VERSION 5.7 ;
  NOWIREEXTENSIONATPIN ON ;
  DIVIDERCHAR "/" ;
  BUSBITCHARS "[]" ;
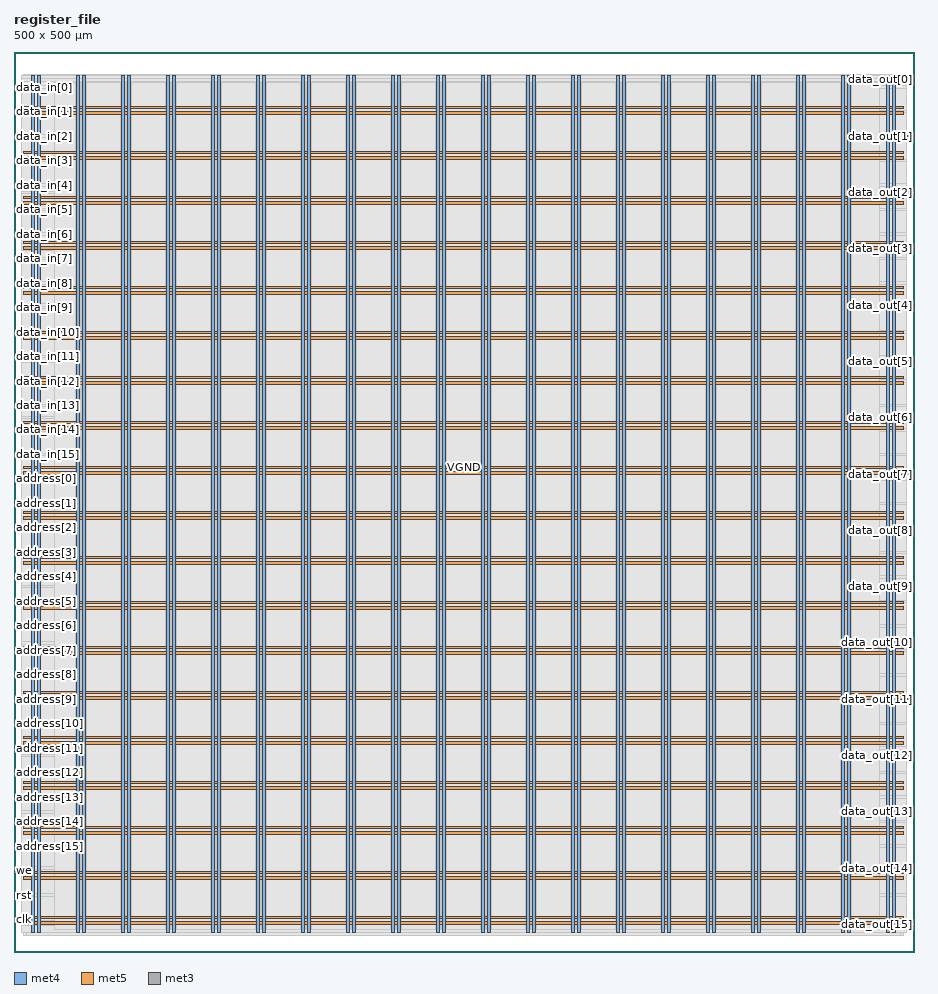
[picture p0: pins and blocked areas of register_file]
MACRO register_file
  CLASS BLOCK ;
  FOREIGN register_file ;
  ORIGIN 0.000 0.000 ;
  SIZE 500.000 BY 500.000 ;
  PIN VGND
    DIRECTION INOUT ;
    USE GROUND ;
    PORT
      LAYER met4 ;
        RECT 13.020 10.640 14.620 487.120 ;
    END
    PORT
      LAYER met4 ;
        RECT 38.020 10.640 39.620 487.120 ;
    END
    PORT
      LAYER met4 ;
        RECT 63.020 10.640 64.620 487.120 ;
    END
    PORT
      LAYER met4 ;
        RECT 88.020 10.640 89.620 487.120 ;
    END
    PORT
      LAYER met4 ;
        RECT 113.020 10.640 114.620 487.120 ;
    END
    PORT
      LAYER met4 ;
        RECT 138.020 10.640 139.620 487.120 ;
    END
    PORT
      LAYER met4 ;
        RECT 163.020 10.640 164.620 487.120 ;
    END
    PORT
      LAYER met4 ;
        RECT 188.020 10.640 189.620 487.120 ;
    END
    PORT
      LAYER met4 ;
        RECT 213.020 10.640 214.620 487.120 ;
    END
    PORT
      LAYER met4 ;
        RECT 238.020 10.640 239.620 487.120 ;
    END
    PORT
      LAYER met4 ;
        RECT 263.020 10.640 264.620 487.120 ;
    END
    PORT
      LAYER met4 ;
        RECT 288.020 10.640 289.620 487.120 ;
    END
    PORT
      LAYER met4 ;
        RECT 313.020 10.640 314.620 487.120 ;
    END
    PORT
      LAYER met4 ;
        RECT 338.020 10.640 339.620 487.120 ;
    END
    PORT
      LAYER met4 ;
        RECT 363.020 10.640 364.620 487.120 ;
    END
    PORT
      LAYER met4 ;
        RECT 388.020 10.640 389.620 487.120 ;
    END
    PORT
      LAYER met4 ;
        RECT 413.020 10.640 414.620 487.120 ;
    END
    PORT
      LAYER met4 ;
        RECT 438.020 10.640 439.620 487.120 ;
    END
    PORT
      LAYER met4 ;
        RECT 463.020 10.640 464.620 487.120 ;
    END
    PORT
      LAYER met4 ;
        RECT 488.020 10.640 489.620 487.120 ;
    END
    PORT
      LAYER met5 ;
        RECT 5.280 18.380 494.280 19.980 ;
    END
    PORT
      LAYER met5 ;
        RECT 5.280 43.380 494.280 44.980 ;
    END
    PORT
      LAYER met5 ;
        RECT 5.280 68.380 494.280 69.980 ;
    END
    PORT
      LAYER met5 ;
        RECT 5.280 93.380 494.280 94.980 ;
    END
    PORT
      LAYER met5 ;
        RECT 5.280 118.380 494.280 119.980 ;
    END
    PORT
      LAYER met5 ;
        RECT 5.280 143.380 494.280 144.980 ;
    END
    PORT
      LAYER met5 ;
        RECT 5.280 168.380 494.280 169.980 ;
    END
    PORT
      LAYER met5 ;
        RECT 5.280 193.380 494.280 194.980 ;
    END
    PORT
      LAYER met5 ;
        RECT 5.280 218.380 494.280 219.980 ;
    END
    PORT
      LAYER met5 ;
        RECT 5.280 243.380 494.280 244.980 ;
    END
    PORT
      LAYER met5 ;
        RECT 5.280 268.380 494.280 269.980 ;
    END
    PORT
      LAYER met5 ;
        RECT 5.280 293.380 494.280 294.980 ;
    END
    PORT
      LAYER met5 ;
        RECT 5.280 318.380 494.280 319.980 ;
    END
    PORT
      LAYER met5 ;
        RECT 5.280 343.380 494.280 344.980 ;
    END
    PORT
      LAYER met5 ;
        RECT 5.280 368.380 494.280 369.980 ;
    END
    PORT
      LAYER met5 ;
        RECT 5.280 393.380 494.280 394.980 ;
    END
    PORT
      LAYER met5 ;
        RECT 5.280 418.380 494.280 419.980 ;
    END
    PORT
      LAYER met5 ;
        RECT 5.280 443.380 494.280 444.980 ;
    END
    PORT
      LAYER met5 ;
        RECT 5.280 468.380 494.280 469.980 ;
    END
  END VGND
  PIN VPWR
    DIRECTION INOUT ;
    USE POWER ;
    PORT
      LAYER met4 ;
        RECT 9.720 10.640 11.320 487.120 ;
    END
    PORT
      LAYER met4 ;
        RECT 34.720 10.640 36.320 487.120 ;
    END
    PORT
      LAYER met4 ;
        RECT 59.720 10.640 61.320 487.120 ;
    END
    PORT
      LAYER met4 ;
        RECT 84.720 10.640 86.320 487.120 ;
    END
    PORT
      LAYER met4 ;
        RECT 109.720 10.640 111.320 487.120 ;
    END
    PORT
      LAYER met4 ;
        RECT 134.720 10.640 136.320 487.120 ;
    END
    PORT
      LAYER met4 ;
        RECT 159.720 10.640 161.320 487.120 ;
    END
    PORT
      LAYER met4 ;
        RECT 184.720 10.640 186.320 487.120 ;
    END
    PORT
      LAYER met4 ;
        RECT 209.720 10.640 211.320 487.120 ;
    END
    PORT
      LAYER met4 ;
        RECT 234.720 10.640 236.320 487.120 ;
    END
    PORT
      LAYER met4 ;
        RECT 259.720 10.640 261.320 487.120 ;
    END
    PORT
      LAYER met4 ;
        RECT 284.720 10.640 286.320 487.120 ;
    END
    PORT
      LAYER met4 ;
        RECT 309.720 10.640 311.320 487.120 ;
    END
    PORT
      LAYER met4 ;
        RECT 334.720 10.640 336.320 487.120 ;
    END
    PORT
      LAYER met4 ;
        RECT 359.720 10.640 361.320 487.120 ;
    END
    PORT
      LAYER met4 ;
        RECT 384.720 10.640 386.320 487.120 ;
    END
    PORT
      LAYER met4 ;
        RECT 409.720 10.640 411.320 487.120 ;
    END
    PORT
      LAYER met4 ;
        RECT 434.720 10.640 436.320 487.120 ;
    END
    PORT
      LAYER met4 ;
        RECT 459.720 10.640 461.320 487.120 ;
    END
    PORT
      LAYER met4 ;
        RECT 484.720 10.640 486.320 487.120 ;
    END
    PORT
      LAYER met5 ;
        RECT 5.280 15.080 494.280 16.680 ;
    END
    PORT
      LAYER met5 ;
        RECT 5.280 40.080 494.280 41.680 ;
    END
    PORT
      LAYER met5 ;
        RECT 5.280 65.080 494.280 66.680 ;
    END
    PORT
      LAYER met5 ;
        RECT 5.280 90.080 494.280 91.680 ;
    END
    PORT
      LAYER met5 ;
        RECT 5.280 115.080 494.280 116.680 ;
    END
    PORT
      LAYER met5 ;
        RECT 5.280 140.080 494.280 141.680 ;
    END
    PORT
      LAYER met5 ;
        RECT 5.280 165.080 494.280 166.680 ;
    END
    PORT
      LAYER met5 ;
        RECT 5.280 190.080 494.280 191.680 ;
    END
    PORT
      LAYER met5 ;
        RECT 5.280 215.080 494.280 216.680 ;
    END
    PORT
      LAYER met5 ;
        RECT 5.280 240.080 494.280 241.680 ;
    END
    PORT
      LAYER met5 ;
        RECT 5.280 265.080 494.280 266.680 ;
    END
    PORT
      LAYER met5 ;
        RECT 5.280 290.080 494.280 291.680 ;
    END
    PORT
      LAYER met5 ;
        RECT 5.280 315.080 494.280 316.680 ;
    END
    PORT
      LAYER met5 ;
        RECT 5.280 340.080 494.280 341.680 ;
    END
    PORT
      LAYER met5 ;
        RECT 5.280 365.080 494.280 366.680 ;
    END
    PORT
      LAYER met5 ;
        RECT 5.280 390.080 494.280 391.680 ;
    END
    PORT
      LAYER met5 ;
        RECT 5.280 415.080 494.280 416.680 ;
    END
    PORT
      LAYER met5 ;
        RECT 5.280 440.080 494.280 441.680 ;
    END
    PORT
      LAYER met5 ;
        RECT 5.280 465.080 494.280 466.680 ;
    END
  END VPWR
  PIN address[0]
    DIRECTION INPUT ;
    USE SIGNAL ;
    ANTENNAGATEAREA 3.813900 ;
    ANTENNADIFFAREA 3.042900 ;
    PORT
      LAYER met3 ;
        RECT 0.000 262.520 4.000 263.120 ;
    END
  END address[0]
  PIN address[10]
    DIRECTION INPUT ;
    USE SIGNAL ;
    PORT
      LAYER met3 ;
        RECT 0.000 126.520 4.000 127.120 ;
    END
  END address[10]
  PIN address[11]
    DIRECTION INPUT ;
    USE SIGNAL ;
    PORT
      LAYER met3 ;
        RECT 0.000 112.920 4.000 113.520 ;
    END
  END address[11]
  PIN address[12]
    DIRECTION INPUT ;
    USE SIGNAL ;
    PORT
      LAYER met3 ;
        RECT 0.000 99.320 4.000 99.920 ;
    END
  END address[12]
  PIN address[13]
    DIRECTION INPUT ;
    USE SIGNAL ;
    PORT
      LAYER met3 ;
        RECT 0.000 85.720 4.000 86.320 ;
    END
  END address[13]
  PIN address[14]
    DIRECTION INPUT ;
    USE SIGNAL ;
    PORT
      LAYER met3 ;
        RECT 0.000 72.120 4.000 72.720 ;
    END
  END address[14]
  PIN address[15]
    DIRECTION INPUT ;
    USE SIGNAL ;
    PORT
      LAYER met3 ;
        RECT 0.000 58.520 4.000 59.120 ;
    END
  END address[15]
  PIN address[1]
    DIRECTION INPUT ;
    USE SIGNAL ;
    ANTENNAGATEAREA 0.645000 ;
    PORT
      LAYER met3 ;
        RECT 0.000 248.920 4.000 249.520 ;
    END
  END address[1]
  PIN address[2]
    DIRECTION INPUT ;
    USE SIGNAL ;
    ANTENNAGATEAREA 0.322500 ;
    PORT
      LAYER met3 ;
        RECT 0.000 235.320 4.000 235.920 ;
    END
  END address[2]
  PIN address[3]
    DIRECTION INPUT ;
    USE SIGNAL ;
    ANTENNAGATEAREA 2.573700 ;
    ANTENNADIFFAREA 0.434700 ;
    PORT
      LAYER met3 ;
        RECT 0.000 221.720 4.000 222.320 ;
    END
  END address[3]
  PIN address[4]
    DIRECTION INPUT ;
    USE SIGNAL ;
    PORT
      LAYER met3 ;
        RECT 0.000 208.120 4.000 208.720 ;
    END
  END address[4]
  PIN address[5]
    DIRECTION INPUT ;
    USE SIGNAL ;
    PORT
      LAYER met3 ;
        RECT 0.000 194.520 4.000 195.120 ;
    END
  END address[5]
  PIN address[6]
    DIRECTION INPUT ;
    USE SIGNAL ;
    PORT
      LAYER met3 ;
        RECT 0.000 180.920 4.000 181.520 ;
    END
  END address[6]
  PIN address[7]
    DIRECTION INPUT ;
    USE SIGNAL ;
    PORT
      LAYER met3 ;
        RECT 0.000 167.320 4.000 167.920 ;
    END
  END address[7]
  PIN address[8]
    DIRECTION INPUT ;
    USE SIGNAL ;
    PORT
      LAYER met3 ;
        RECT 0.000 153.720 4.000 154.320 ;
    END
  END address[8]
  PIN address[9]
    DIRECTION INPUT ;
    USE SIGNAL ;
    PORT
      LAYER met3 ;
        RECT 0.000 140.120 4.000 140.720 ;
    END
  END address[9]
  PIN clk
    DIRECTION INPUT ;
    USE SIGNAL ;
    ANTENNAGATEAREA 1.286700 ;
    ANTENNADIFFAREA 0.434700 ;
    PORT
      LAYER met3 ;
        RECT 0.000 17.720 4.000 18.320 ;
    END
  END clk
  PIN data_in[0]
    DIRECTION INPUT ;
    USE SIGNAL ;
    ANTENNAGATEAREA 1.681500 ;
    PORT
      LAYER met3 ;
        RECT 0.000 480.120 4.000 480.720 ;
    END
  END data_in[0]
  PIN data_in[10]
    DIRECTION INPUT ;
    USE SIGNAL ;
    ANTENNAGATEAREA 1.681500 ;
    PORT
      LAYER met3 ;
        RECT 0.000 344.120 4.000 344.720 ;
    END
  END data_in[10]
  PIN data_in[11]
    DIRECTION INPUT ;
    USE SIGNAL ;
    ANTENNAGATEAREA 2.985600 ;
    ANTENNADIFFAREA 1.304100 ;
    PORT
      LAYER met3 ;
        RECT 0.000 330.520 4.000 331.120 ;
    END
  END data_in[11]
  PIN data_in[12]
    DIRECTION INPUT ;
    USE SIGNAL ;
    ANTENNAGATEAREA 1.681500 ;
    PORT
      LAYER met3 ;
        RECT 0.000 316.920 4.000 317.520 ;
    END
  END data_in[12]
  PIN data_in[13]
    DIRECTION INPUT ;
    USE SIGNAL ;
    ANTENNAGATEAREA 1.681500 ;
    PORT
      LAYER met3 ;
        RECT 0.000 303.320 4.000 303.920 ;
    END
  END data_in[13]
  PIN data_in[14]
    DIRECTION INPUT ;
    USE SIGNAL ;
    ANTENNAGATEAREA 1.681500 ;
    PORT
      LAYER met3 ;
        RECT 0.000 289.720 4.000 290.320 ;
    END
  END data_in[14]
  PIN data_in[15]
    DIRECTION INPUT ;
    USE SIGNAL ;
    ANTENNAGATEAREA 1.681500 ;
    PORT
      LAYER met3 ;
        RECT 0.000 276.120 4.000 276.720 ;
    END
  END data_in[15]
  PIN data_in[1]
    DIRECTION INPUT ;
    USE SIGNAL ;
    ANTENNAGATEAREA 2.550900 ;
    ANTENNADIFFAREA 0.869400 ;
    PORT
      LAYER met3 ;
        RECT 0.000 466.520 4.000 467.120 ;
    END
  END data_in[1]
  PIN data_in[2]
    DIRECTION INPUT ;
    USE SIGNAL ;
    ANTENNAGATEAREA 1.681500 ;
    PORT
      LAYER met3 ;
        RECT 0.000 452.920 4.000 453.520 ;
    END
  END data_in[2]
  PIN data_in[3]
    DIRECTION INPUT ;
    USE SIGNAL ;
    ANTENNAGATEAREA 1.681500 ;
    PORT
      LAYER met3 ;
        RECT 0.000 439.320 4.000 439.920 ;
    END
  END data_in[3]
  PIN data_in[4]
    DIRECTION INPUT ;
    USE SIGNAL ;
    ANTENNAGATEAREA 1.681500 ;
    PORT
      LAYER met3 ;
        RECT 0.000 425.720 4.000 426.320 ;
    END
  END data_in[4]
  PIN data_in[5]
    DIRECTION INPUT ;
    USE SIGNAL ;
    ANTENNAGATEAREA 2.550900 ;
    ANTENNADIFFAREA 0.869400 ;
    PORT
      LAYER met3 ;
        RECT 0.000 412.120 4.000 412.720 ;
    END
  END data_in[5]
  PIN data_in[6]
    DIRECTION INPUT ;
    USE SIGNAL ;
    ANTENNAGATEAREA 1.681500 ;
    PORT
      LAYER met3 ;
        RECT 0.000 398.520 4.000 399.120 ;
    END
  END data_in[6]
  PIN data_in[7]
    DIRECTION INPUT ;
    USE SIGNAL ;
    ANTENNAGATEAREA 1.681500 ;
    PORT
      LAYER met3 ;
        RECT 0.000 384.920 4.000 385.520 ;
    END
  END data_in[7]
  PIN data_in[8]
    DIRECTION INPUT ;
    USE SIGNAL ;
    ANTENNAGATEAREA 1.681500 ;
    PORT
      LAYER met3 ;
        RECT 0.000 371.320 4.000 371.920 ;
    END
  END data_in[8]
  PIN data_in[9]
    DIRECTION INPUT ;
    USE SIGNAL ;
    ANTENNAGATEAREA 1.681500 ;
    PORT
      LAYER met3 ;
        RECT 0.000 357.720 4.000 358.320 ;
    END
  END data_in[9]
  PIN data_out[0]
    DIRECTION OUTPUT TRISTATE ;
    USE SIGNAL ;
    ANTENNADIFFAREA 0.445500 ;
    PORT
      LAYER met3 ;
        RECT 496.000 484.200 500.000 484.800 ;
    END
  END data_out[0]
  PIN data_out[10]
    DIRECTION OUTPUT TRISTATE ;
    USE SIGNAL ;
    ANTENNADIFFAREA 0.445500 ;
    PORT
      LAYER met3 ;
        RECT 496.000 171.400 500.000 172.000 ;
    END
  END data_out[10]
  PIN data_out[11]
    DIRECTION OUTPUT TRISTATE ;
    USE SIGNAL ;
    ANTENNADIFFAREA 0.445500 ;
    PORT
      LAYER met3 ;
        RECT 496.000 140.120 500.000 140.720 ;
    END
  END data_out[11]
  PIN data_out[12]
    DIRECTION OUTPUT TRISTATE ;
    USE SIGNAL ;
    ANTENNADIFFAREA 0.445500 ;
    PORT
      LAYER met3 ;
        RECT 496.000 108.840 500.000 109.440 ;
    END
  END data_out[12]
  PIN data_out[13]
    DIRECTION OUTPUT TRISTATE ;
    USE SIGNAL ;
    ANTENNADIFFAREA 0.445500 ;
    PORT
      LAYER met3 ;
        RECT 496.000 77.560 500.000 78.160 ;
    END
  END data_out[13]
  PIN data_out[14]
    DIRECTION OUTPUT TRISTATE ;
    USE SIGNAL ;
    ANTENNADIFFAREA 0.445500 ;
    PORT
      LAYER met3 ;
        RECT 496.000 46.280 500.000 46.880 ;
    END
  END data_out[14]
  PIN data_out[15]
    DIRECTION OUTPUT TRISTATE ;
    USE SIGNAL ;
    ANTENNADIFFAREA 0.445500 ;
    PORT
      LAYER met3 ;
        RECT 496.000 15.000 500.000 15.600 ;
    END
  END data_out[15]
  PIN data_out[1]
    DIRECTION OUTPUT TRISTATE ;
    USE SIGNAL ;
    ANTENNADIFFAREA 0.445500 ;
    PORT
      LAYER met3 ;
        RECT 496.000 452.920 500.000 453.520 ;
    END
  END data_out[1]
  PIN data_out[2]
    DIRECTION OUTPUT TRISTATE ;
    USE SIGNAL ;
    ANTENNADIFFAREA 0.445500 ;
    PORT
      LAYER met3 ;
        RECT 496.000 421.640 500.000 422.240 ;
    END
  END data_out[2]
  PIN data_out[3]
    DIRECTION OUTPUT TRISTATE ;
    USE SIGNAL ;
    ANTENNADIFFAREA 0.445500 ;
    PORT
      LAYER met3 ;
        RECT 496.000 390.360 500.000 390.960 ;
    END
  END data_out[3]
  PIN data_out[4]
    DIRECTION OUTPUT TRISTATE ;
    USE SIGNAL ;
    ANTENNADIFFAREA 0.445500 ;
    PORT
      LAYER met3 ;
        RECT 496.000 359.080 500.000 359.680 ;
    END
  END data_out[4]
  PIN data_out[5]
    DIRECTION OUTPUT TRISTATE ;
    USE SIGNAL ;
    ANTENNADIFFAREA 0.445500 ;
    PORT
      LAYER met3 ;
        RECT 496.000 327.800 500.000 328.400 ;
    END
  END data_out[5]
  PIN data_out[6]
    DIRECTION OUTPUT TRISTATE ;
    USE SIGNAL ;
    ANTENNADIFFAREA 0.445500 ;
    PORT
      LAYER met3 ;
        RECT 496.000 296.520 500.000 297.120 ;
    END
  END data_out[6]
  PIN data_out[7]
    DIRECTION OUTPUT TRISTATE ;
    USE SIGNAL ;
    ANTENNADIFFAREA 0.445500 ;
    PORT
      LAYER met3 ;
        RECT 496.000 265.240 500.000 265.840 ;
    END
  END data_out[7]
  PIN data_out[8]
    DIRECTION OUTPUT TRISTATE ;
    USE SIGNAL ;
    ANTENNADIFFAREA 0.445500 ;
    PORT
      LAYER met3 ;
        RECT 496.000 233.960 500.000 234.560 ;
    END
  END data_out[8]
  PIN data_out[9]
    DIRECTION OUTPUT TRISTATE ;
    USE SIGNAL ;
    ANTENNADIFFAREA 0.445500 ;
    PORT
      LAYER met3 ;
        RECT 496.000 202.680 500.000 203.280 ;
    END
  END data_out[9]
  PIN rst
    DIRECTION INPUT ;
    USE SIGNAL ;
    ANTENNAGATEAREA 1.812900 ;
    ANTENNADIFFAREA 0.869400 ;
    PORT
      LAYER met3 ;
        RECT 0.000 31.320 4.000 31.920 ;
    END
  END rst
  PIN we
    DIRECTION INPUT ;
    USE SIGNAL ;
    ANTENNAGATEAREA 4.233600 ;
    ANTENNADIFFAREA 3.477600 ;
    PORT
      LAYER met3 ;
        RECT 0.000 44.920 4.000 45.520 ;
    END
  END we
  OBS
      LAYER li1 ;
        RECT 5.520 10.795 494.040 486.965 ;
      LAYER met1 ;
        RECT 5.520 9.220 494.040 487.520 ;
      LAYER met2 ;
        RECT 7.000 9.190 492.560 487.550 ;
      LAYER met3 ;
        RECT 4.000 485.200 496.000 487.045 ;
        RECT 4.000 483.800 495.600 485.200 ;
        RECT 4.000 481.120 496.000 483.800 ;
        RECT 4.400 479.720 496.000 481.120 ;
        RECT 4.000 467.520 496.000 479.720 ;
        RECT 4.400 466.120 496.000 467.520 ;
        RECT 4.000 453.920 496.000 466.120 ;
        RECT 4.400 452.520 495.600 453.920 ;
        RECT 4.000 440.320 496.000 452.520 ;
        RECT 4.400 438.920 496.000 440.320 ;
        RECT 4.000 426.720 496.000 438.920 ;
        RECT 4.400 425.320 496.000 426.720 ;
        RECT 4.000 422.640 496.000 425.320 ;
        RECT 4.000 421.240 495.600 422.640 ;
        RECT 4.000 413.120 496.000 421.240 ;
        RECT 4.400 411.720 496.000 413.120 ;
        RECT 4.000 399.520 496.000 411.720 ;
        RECT 4.400 398.120 496.000 399.520 ;
        RECT 4.000 391.360 496.000 398.120 ;
        RECT 4.000 389.960 495.600 391.360 ;
        RECT 4.000 385.920 496.000 389.960 ;
        RECT 4.400 384.520 496.000 385.920 ;
        RECT 4.000 372.320 496.000 384.520 ;
        RECT 4.400 370.920 496.000 372.320 ;
        RECT 4.000 360.080 496.000 370.920 ;
        RECT 4.000 358.720 495.600 360.080 ;
        RECT 4.400 358.680 495.600 358.720 ;
        RECT 4.400 357.320 496.000 358.680 ;
        RECT 4.000 345.120 496.000 357.320 ;
        RECT 4.400 343.720 496.000 345.120 ;
        RECT 4.000 331.520 496.000 343.720 ;
        RECT 4.400 330.120 496.000 331.520 ;
        RECT 4.000 328.800 496.000 330.120 ;
        RECT 4.000 327.400 495.600 328.800 ;
        RECT 4.000 317.920 496.000 327.400 ;
        RECT 4.400 316.520 496.000 317.920 ;
        RECT 4.000 304.320 496.000 316.520 ;
        RECT 4.400 302.920 496.000 304.320 ;
        RECT 4.000 297.520 496.000 302.920 ;
        RECT 4.000 296.120 495.600 297.520 ;
        RECT 4.000 290.720 496.000 296.120 ;
        RECT 4.400 289.320 496.000 290.720 ;
        RECT 4.000 277.120 496.000 289.320 ;
        RECT 4.400 275.720 496.000 277.120 ;
        RECT 4.000 266.240 496.000 275.720 ;
        RECT 4.000 264.840 495.600 266.240 ;
        RECT 4.000 263.520 496.000 264.840 ;
        RECT 4.400 262.120 496.000 263.520 ;
        RECT 4.000 249.920 496.000 262.120 ;
        RECT 4.400 248.520 496.000 249.920 ;
        RECT 4.000 236.320 496.000 248.520 ;
        RECT 4.400 234.960 496.000 236.320 ;
        RECT 4.400 234.920 495.600 234.960 ;
        RECT 4.000 233.560 495.600 234.920 ;
        RECT 4.000 222.720 496.000 233.560 ;
        RECT 4.400 221.320 496.000 222.720 ;
        RECT 4.000 209.120 496.000 221.320 ;
        RECT 4.400 207.720 496.000 209.120 ;
        RECT 4.000 203.680 496.000 207.720 ;
        RECT 4.000 202.280 495.600 203.680 ;
        RECT 4.000 195.520 496.000 202.280 ;
        RECT 4.400 194.120 496.000 195.520 ;
        RECT 4.000 181.920 496.000 194.120 ;
        RECT 4.400 180.520 496.000 181.920 ;
        RECT 4.000 172.400 496.000 180.520 ;
        RECT 4.000 171.000 495.600 172.400 ;
        RECT 4.000 168.320 496.000 171.000 ;
        RECT 4.400 166.920 496.000 168.320 ;
        RECT 4.000 154.720 496.000 166.920 ;
        RECT 4.400 153.320 496.000 154.720 ;
        RECT 4.000 141.120 496.000 153.320 ;
        RECT 4.400 139.720 495.600 141.120 ;
        RECT 4.000 127.520 496.000 139.720 ;
        RECT 4.400 126.120 496.000 127.520 ;
        RECT 4.000 113.920 496.000 126.120 ;
        RECT 4.400 112.520 496.000 113.920 ;
        RECT 4.000 109.840 496.000 112.520 ;
        RECT 4.000 108.440 495.600 109.840 ;
        RECT 4.000 100.320 496.000 108.440 ;
        RECT 4.400 98.920 496.000 100.320 ;
        RECT 4.000 86.720 496.000 98.920 ;
        RECT 4.400 85.320 496.000 86.720 ;
        RECT 4.000 78.560 496.000 85.320 ;
        RECT 4.000 77.160 495.600 78.560 ;
        RECT 4.000 73.120 496.000 77.160 ;
        RECT 4.400 71.720 496.000 73.120 ;
        RECT 4.000 59.520 496.000 71.720 ;
        RECT 4.400 58.120 496.000 59.520 ;
        RECT 4.000 47.280 496.000 58.120 ;
        RECT 4.000 45.920 495.600 47.280 ;
        RECT 4.400 45.880 495.600 45.920 ;
        RECT 4.400 44.520 496.000 45.880 ;
        RECT 4.000 32.320 496.000 44.520 ;
        RECT 4.400 30.920 496.000 32.320 ;
        RECT 4.000 18.720 496.000 30.920 ;
        RECT 4.400 17.320 496.000 18.720 ;
        RECT 4.000 16.000 496.000 17.320 ;
        RECT 4.000 14.600 495.600 16.000 ;
        RECT 4.000 10.715 496.000 14.600 ;
      LAYER met4 ;
        RECT 22.375 12.415 34.320 483.305 ;
        RECT 36.720 12.415 37.620 483.305 ;
        RECT 40.020 12.415 59.320 483.305 ;
        RECT 61.720 12.415 62.620 483.305 ;
        RECT 65.020 12.415 84.320 483.305 ;
        RECT 86.720 12.415 87.620 483.305 ;
        RECT 90.020 12.415 109.320 483.305 ;
        RECT 111.720 12.415 112.620 483.305 ;
        RECT 115.020 12.415 134.320 483.305 ;
        RECT 136.720 12.415 137.620 483.305 ;
        RECT 140.020 12.415 159.320 483.305 ;
        RECT 161.720 12.415 162.620 483.305 ;
        RECT 165.020 12.415 184.320 483.305 ;
        RECT 186.720 12.415 187.620 483.305 ;
        RECT 190.020 12.415 209.320 483.305 ;
        RECT 211.720 12.415 212.620 483.305 ;
        RECT 215.020 12.415 234.320 483.305 ;
        RECT 236.720 12.415 237.620 483.305 ;
        RECT 240.020 12.415 259.320 483.305 ;
        RECT 261.720 12.415 262.620 483.305 ;
        RECT 265.020 12.415 284.320 483.305 ;
        RECT 286.720 12.415 287.620 483.305 ;
        RECT 290.020 12.415 309.320 483.305 ;
        RECT 311.720 12.415 312.620 483.305 ;
        RECT 315.020 12.415 334.320 483.305 ;
        RECT 336.720 12.415 337.620 483.305 ;
        RECT 340.020 12.415 359.320 483.305 ;
        RECT 361.720 12.415 362.620 483.305 ;
        RECT 365.020 12.415 384.320 483.305 ;
        RECT 386.720 12.415 387.620 483.305 ;
        RECT 390.020 12.415 409.320 483.305 ;
        RECT 411.720 12.415 412.620 483.305 ;
        RECT 415.020 12.415 434.320 483.305 ;
        RECT 436.720 12.415 437.620 483.305 ;
        RECT 440.020 12.415 459.320 483.305 ;
        RECT 461.720 12.415 462.620 483.305 ;
        RECT 465.020 12.415 480.865 483.305 ;
  END
END register_file
END LIBRARY

